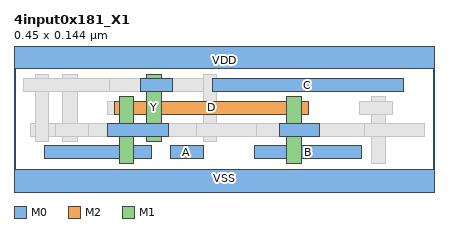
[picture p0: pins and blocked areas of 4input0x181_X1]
MACRO 4input0x181_X1
  CLASS CORE ;
  ORIGIN 0 0 ;
  FOREIGN 4input0x181_X1 0 0 ;
  SIZE 0.4500 BY 0.1440 ;
  SYMMETRY X Y ;
  SITE coresite ;
  PIN A
    DIRECTION INPUT ;
    USE SIGNAL ;
    PORT
      LAYER M0 ;
        RECT 0.1680 0.0290 0.2025 0.0430 ;
    END
  END A
  PIN B
    DIRECTION INPUT ;
    USE SIGNAL ;
    PORT
      LAYER M0 ;
        RECT 0.2580 0.0290 0.3720 0.0430 ;
    END
  END B
  PIN C
    DIRECTION INPUT ;
    USE SIGNAL ;
    PORT
      LAYER M0 ;
        RECT 0.2130 0.1010 0.4170 0.1150 ;
    END
  END C
  PIN D
    DIRECTION INPUT ;
    USE SIGNAL ;
    PORT
      LAYER M2 ;
        RECT 0.1080 0.0770 0.3150 0.0910 ;
      LAYER M1 ;
        RECT 0.1125 0.0240 0.1275 0.0960 ;
        RECT 0.2925 0.0240 0.3075 0.0960 ;
      LAYER M0 ;
        RECT 0.2850 0.0530 0.3270 0.0670 ;
        RECT 0.0330 0.0290 0.1470 0.0430 ;
    END
  END D
  PIN Y
    DIRECTION OUTPUT ;
    USE SIGNAL ;
    PORT
      LAYER M1 ;
        RECT 0.1425 0.0480 0.1575 0.1200 ;
      LAYER M0 ;
        RECT 0.1350 0.1010 0.1695 0.1150 ;
        RECT 0.1005 0.0530 0.1650 0.0670 ;
    END
  END Y
  PIN VDD
    DIRECTION INOUT ;
    USE POWER ;
    SHAPE ABUTMENT ;
    PORT
      LAYER M0 ;
        RECT 0.0000 0.1260 0.4500 0.1620 ;
    END
  END VDD
  PIN VSS
    DIRECTION INOUT ;
    USE GROUND ;
    SHAPE ABUTMENT ;
    PORT
      LAYER M0 ;
        RECT 0.0000 -0.0180 0.4500 0.0180 ;
    END
  END VSS
  OBS
    LAYER M2 ;
      RECT 0.0180 0.0530 0.4050 0.0670 ;
      RECT 0.0450 0.1010 0.2250 0.1150 ;
    LAYER V1 ;
      RECT 0.0530 0.1010 0.0670 0.1150 ;
      RECT 0.2030 0.1010 0.2170 0.1150 ;
      RECT 0.1130 0.0770 0.1270 0.0910 ;
      RECT 0.2930 0.0770 0.3070 0.0910 ;
      RECT 0.0230 0.0530 0.0370 0.0670 ;
      RECT 0.3830 0.0530 0.3970 0.0670 ;
    LAYER M1 ;
      RECT 0.3825 0.0240 0.3975 0.0960 ;
      RECT 0.0225 0.0480 0.0375 0.1200 ;
      RECT 0.0525 0.0480 0.0675 0.1200 ;
      RECT 0.2025 0.0480 0.2175 0.1200 ;
    LAYER V0 ;
      RECT 0.0530 0.0530 0.0670 0.0670 ;
      RECT 0.2030 0.0530 0.2170 0.0670 ;
      RECT 0.1430 0.1010 0.1570 0.1150 ;
      RECT 0.1430 0.0530 0.1570 0.0670 ;
      RECT 0.1130 0.0290 0.1270 0.0430 ;
      RECT 0.2930 0.0530 0.3070 0.0670 ;
      RECT 0.0230 0.1010 0.0370 0.1150 ;
      RECT 0.3830 0.0770 0.3970 0.0910 ;
      RECT 0.3830 0.0530 0.3970 0.0670 ;
    LAYER M0 ;
      RECT 0.0450 0.0530 0.0795 0.0670 ;
      RECT 0.1950 0.0530 0.2595 0.0670 ;
      RECT 0.3750 0.0530 0.4395 0.0670 ;
      RECT 0.1005 0.0770 0.2145 0.0910 ;
      RECT 0.3705 0.0770 0.4050 0.0910 ;
      RECT 0.0105 0.1010 0.1020 0.1150 ;
  END
END 4input0x181_X1
